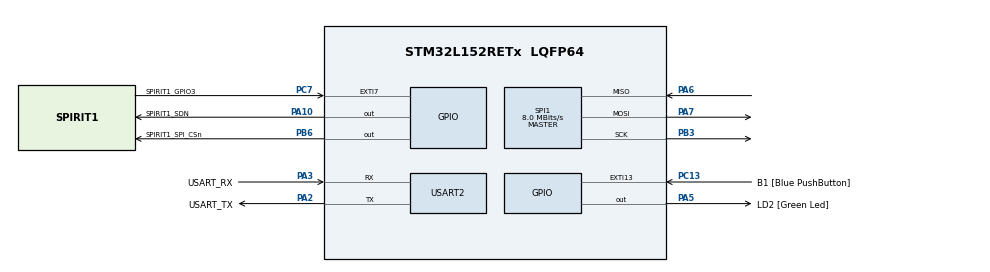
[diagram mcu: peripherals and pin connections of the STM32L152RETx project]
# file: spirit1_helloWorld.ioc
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Mcu.Family=STM32L1
Mcu.Name=STM32L152RETx
Mcu.Package=LQFP64
NVIC.EXTI15_10_IRQn=true\:0\:0\:false\:false\:true\:true\:true\:true
NVIC.EXTI9_5_IRQn=true\:0\:0\:false\:false\:true\:true\:true\:true
NVIC.PriorityGroup=NVIC_PRIORITYGROUP_0
PA10.GPIO_Label=SPIRIT1_SDN
PA10.Signal=GPIO_Output
PA13.GPIO_Label=TMS
PA13.Mode=Serial_Wire
PA13.Signal=SYS_JTMS-SWDIO
PA14.GPIO_Label=TCK
PA14.Mode=Serial_Wire
PA14.Signal=SYS_JTCK-SWCLK
PA2.GPIO_Label=USART_TX
PA2.Mode=Asynchronous
PA2.Signal=USART2_TX
PA3.GPIO_Label=USART_RX
PA3.Mode=Asynchronous
PA3.Signal=USART2_RX
PA5.GPIO_Label=LD2 [Green Led]
PA5.Signal=GPIO_Output
PA6.Mode=Full_Duplex_Master
PA6.Signal=SPI1_MISO
PA7.Mode=Full_Duplex_Master
PA7.Signal=SPI1_MOSI
PB3.Mode=Full_Duplex_Master
PB3.Signal=SPI1_SCK
PB6.GPIO_Label=SPIRIT1_SPI_CSn
PB6.Signal=GPIO_Output
PC13-WKUP2.GPIO_Label=B1 [Blue PushButton]
PC13-WKUP2.Signal=GPXTI13
PC14-OSC32_IN.Mode=LSE-External-Oscillator
PC14-OSC32_IN.Signal=RCC_OSC32_IN
PC15-OSC32_OUT.Mode=LSE-External-Oscillator
PC15-OSC32_OUT.Signal=RCC_OSC32_OUT
PC7.GPIO_Label=SPIRIT1_GPIO3
PC7.GPIO_ModeDefaultEXTI=GPIO_MODE_IT_FALLING
PC7.Signal=GPXTI7
PH0-OSC_IN.Mode=HSE-External-Clock-Source
PH0-OSC_IN.Signal=RCC_OSC_IN
PH1-OSC_OUT.Signal=RCC_OSC_OUT
ProjectManager.HeapSize=0x200
ProjectManager.StackSize=0x400
ProjectManager.TargetToolchain=STM32CubeIDE
RCC.48MHZClocksFreq_Value=48000000
RCC.AHBFreq_Value=32000000
RCC.APB1Freq_Value=32000000
RCC.APB1TimFreq_Value=32000000
RCC.APB2Freq_Value=32000000
RCC.APB2TimFreq_Value=32000000
RCC.HCLKFreq_Value=32000000
RCC.HSE_VALUE=8000000
RCC.HSI_VALUE=16000000
RCC.MSI_VALUE=2097000
RCC.PLLDIV=RCC_PLL_DIV3
RCC.PLLMUL=RCC_PLL_MUL6
RCC.RTCClockSelectionVirtual=RCC_RTCCLKSOURCE_LSE
RCC.SYSCLKFreq_VALUE=32000000
RCC.SYSCLKSource=RCC_SYSCLKSOURCE_PLLCLK
RCC.USBOutput=48000000
RCC.VCOOutputFreq_Value=96000000
SPI1.BaudRatePrescaler=SPI_BAUDRATEPRESCALER_4
SPI1.CalculateBaudRate=8.0 MBits/s
SPI1.Direction=SPI_DIRECTION_2LINES
SPI1.Mode=SPI_MODE_MASTER
SPI1.VirtualType=VM_MASTER
USART2.VirtualMode=VM_ASYNC
board=NUCLEO-L152RE

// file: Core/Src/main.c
/* USER CODE BEGIN Header */
/**
  ******************************************************************************
  * @file           : main.c
  * @brief          : Main program body
  ******************************************************************************
  * @attention
  *
  * <h2><center>&copy; Copyright (c) 2021 STMicroelectronics.
  * All rights reserved.</center></h2>
  *
  * This software component is licensed by ST under BSD 3-Clause license,
  * the "License"; You may not use this file except in compliance with the
  * License. You may obtain a copy of the License at:
  *                        opensource.org/licenses/BSD-3-Clause
  *
  ******************************************************************************
  */
/* USER CODE END Header */
#include "main.h"
#include "spi.h"
#include "usart.h"
#include "gpio.h"

/* USER CODE BEGIN Includes */

#include <stdio.h>
#include "spsgrf.h"

/* USER CODE END Includes */

/* USER CODE BEGIN PD */

//#define APPLICATION_TRANSMITTER // comment out if programming the receiver

/* USER CODE END PD */

/* USER CODE BEGIN PV */

volatile SpiritFlagStatus xTxDoneFlag;
volatile SpiritFlagStatus xRxDoneFlag;

/* USER CODE END PV */

void SystemClock_Config(void);

int main(void)
{
  /* USER CODE BEGIN 1 */

  char payload[20] = "Hello World!\r\n";
  uint8_t rxLen;

  /* USER CODE END 1 */

  /* MCU Configuration--------------------------------------------------------*/

  /* Reset of all peripherals, Initializes the Flash interface and the Systick. */
  HAL_Init();

  /* Configure the system clock */
  SystemClock_Config();

  /* Initialize all configured peripherals */
  MX_GPIO_Init();
  MX_USART2_UART_Init();
  MX_SPI1_Init();
  /* USER CODE BEGIN 2 */

  SPSGRF_Init();
  SpiritPktBasicSetDestinationAddress(0x44);

  /* USER CODE END 2 */

  /* Infinite loop */
  while (1)
  {

    /* USER CODE BEGIN 3 */

#ifdef APPLICATION_TRANSMITTER
    // Send the payload
    xTxDoneFlag = S_RESET;
    HAL_UART_Transmit(&huart2, "before while\r\n", 14, HAL_MAX_DELAY);
    SPSGRF_StartTx(payload, strlen(payload));
    HAL_UART_Transmit(&huart2, "Entering while\r\n", 14, HAL_MAX_DELAY);

    while(!xTxDoneFlag);
    HAL_UART_Transmit(&huart2, "Payload Sent\r\n", 14, HAL_MAX_DELAY); // Never getting here

    HAL_Delay(2000); // Block for 2000 ms
#else
    xRxDoneFlag = S_RESET;
    SPSGRF_StartRx();
    HAL_UART_Transmit(&huart2, "Waiting to receive\r\n", 14, HAL_MAX_DELAY);
    while (!xRxDoneFlag);
    HAL_UART_Transmit(&huart2, "After loop\r\n", 14, HAL_MAX_DELAY);
    rxLen = SPSGRF_GetRxData(payload);
    HAL_UART_Transmit(&huart2, "Received: ", 10, HAL_MAX_DELAY); // Never getting here
    HAL_UART_Transmit(&huart2, payload, rxLen, HAL_MAX_DELAY);
#endif // APPLICATION_TRANSMITTER
  }
  /* USER CODE END 3 */
}

void SystemClock_Config(void)
{
  RCC_OscInitTypeDef RCC_OscInitStruct = {0};
  RCC_ClkInitTypeDef RCC_ClkInitStruct = {0};

  /** Configure the main internal regulator output voltage
  */
  if (HAL_PWREx_ControlVoltageScaling(PWR_REGULATOR_VOLTAGE_SCALE1) != HAL_OK)
  {
    Error_Handler();
  }

  /** Initializes the RCC Oscillators according to the specified parameters
  * in the RCC_OscInitTypeDef structure.
  */
  RCC_OscInitStruct.OscillatorType = RCC_OSCILLATORTYPE_HSI;
  RCC_OscInitStruct.HSIState = RCC_HSI_ON;
  RCC_OscInitStruct.HSICalibrationValue = RCC_HSICALIBRATION_DEFAULT;
  RCC_OscInitStruct.PLL.PLLState = RCC_PLL_ON;
  RCC_OscInitStruct.PLL.PLLSource = RCC_PLLSOURCE_HSI;
  RCC_OscInitStruct.PLL.PLLM = 1;
  RCC_OscInitStruct.PLL.PLLN = 10;
  RCC_OscInitStruct.PLL.PLLP = RCC_PLLP_DIV7;
  RCC_OscInitStruct.PLL.PLLQ = RCC_PLLQ_DIV2;
  RCC_OscInitStruct.PLL.PLLR = RCC_PLLR_DIV2;
  if (HAL_RCC_OscConfig(&RCC_OscInitStruct) != HAL_OK)
  {
    Error_Handler();
  }

  /** Initializes the CPU, AHB and APB buses clocks
  */
  RCC_ClkInitStruct.ClockType = RCC_CLOCKTYPE_HCLK|RCC_CLOCKTYPE_SYSCLK
                              |RCC_CLOCKTYPE_PCLK1|RCC_CLOCKTYPE_PCLK2;
  RCC_ClkInitStruct.SYSCLKSource = RCC_SYSCLKSOURCE_PLLCLK;
  RCC_ClkInitStruct.AHBCLKDivider = RCC_SYSCLK_DIV1;
  RCC_ClkInitStruct.APB1CLKDivider = RCC_HCLK_DIV1;
  RCC_ClkInitStruct.APB2CLKDivider = RCC_HCLK_DIV1;

  if (HAL_RCC_ClockConfig(&RCC_ClkInitStruct, FLASH_LATENCY_4) != HAL_OK)
  {
    Error_Handler();
  }
}

/* USER CODE BEGIN 4 */

void EXTI0_IRQHandler(void){
	SpiritIrqs xIrqStatus;
	HAL_UART_Transmit(&huart2, "Interrupt called\r\n", 14, HAL_MAX_DELAY);
	SpiritIrqGetStatus(&xIrqStatus);
	  if (xIrqStatus.IRQ_TX_DATA_SENT)
	  {
	    xTxDoneFlag = S_SET;
	  }
	  if (xIrqStatus.IRQ_RX_DATA_READY)
	  {
	    xRxDoneFlag = S_SET;
	  }
    if (EXTI->PR1 & 0x1){
        EXTI->PR1 |= 0x1; //clear flag by writing to it
        GPIOA->BSRR = 0x1 << 5; //turn on LED
    }
}

void HAL_GPIO_EXTI_Callback(uint16_t GPIO_Pin)
{
    HAL_GPIO_WritePin(GPIOA, GPIO_PIN_5, GPIO_PIN_SET);

  SpiritIrqs xIrqStatus;
  HAL_UART_Transmit(&huart2, "Interrupt called\r\n", 14, HAL_MAX_DELAY);
  if (GPIO_Pin != SPIRIT1_GPIO3_Pin)
  {
    return;
  }

  SpiritIrqGetStatus(&xIrqStatus);
  if (xIrqStatus.IRQ_TX_DATA_SENT)
  {
    xTxDoneFlag = S_SET;
  }
  if (xIrqStatus.IRQ_RX_DATA_READY)
  {
    xRxDoneFlag = S_SET;
  }
  if (xIrqStatus.IRQ_RX_DATA_DISC || xIrqStatus.IRQ_RX_TIMEOUT)
  {
    SpiritCmdStrobeSabort();
  }
}

/* USER CODE END 4 */

void Error_Handler(void)
{
  __disable_irq();
  while (1)
  {
  }
}
